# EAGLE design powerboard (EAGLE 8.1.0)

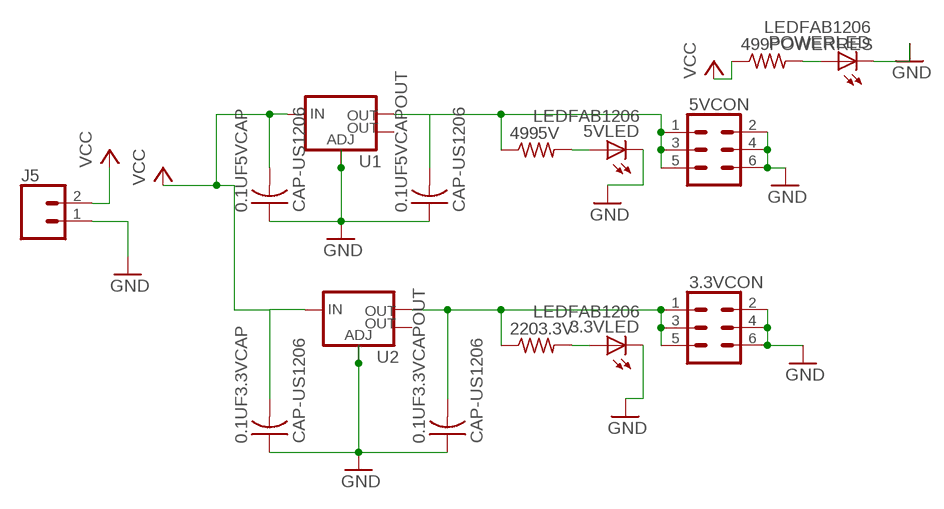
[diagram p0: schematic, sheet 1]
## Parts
0.1UF3.3VCAP  CAP-US1206  [C1206]
0.1UF3.3VCAPOUT  CAP-US1206  [C1206]
0.1UF5VCAP  CAP-US1206  [C1206]
0.1UF5VCAPOUT  CAP-US1206  [C1206]
3.3VCON  CONN_03X22X3_SILK_MALE_PTH  [2X3]
3.3VLED  LEDFAB1206  [LED1206FAB]
5VCON  CONN_03X22X3_SILK_MALE_PTH  [2X3]
5VLED  LEDFAB1206  [LED1206FAB]
499POWERRES  RES-US1206FAB  [R1206FAB]
2203.3V  RES-US1206FAB  [R1206FAB]
4995V  RES-US1206FAB  [R1206FAB]
J5  CONN_02PTH3  [1X02_LONGPADS]
POWERLED  LEDFAB1206  [LED1206FAB]
U1  V_REG_LM1117SOT223  [SOT223]
U2  V_REG_LM1117SOT223  [SOT223]

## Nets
3.3VOUT: 0.1UF3.3VCAPOUT.2 3.3VCON.1 3.3VCON.3 3.3VCON.5 2203.3V.1 U2.2(OUT)
5VOUT: 0.1UF5VCAPOUT.2 5VCON.1 5VCON.3 5VCON.5 4995V.1 U1.2(OUT)
GND: 0.1UF3.3VCAP.1 0.1UF3.3VCAPOUT.1 0.1UF5VCAP.1 0.1UF5VCAPOUT.1 3.3VCON.2 3.3VCON.4 3.3VCON.6 3.3VLED.2(C) 5VCON.2 5VCON.4 5VCON.6 5VLED.2(C) J5.1 POWERLED.2(C) U1.1(ADJ) U2.1(ADJ)
N$1: 5VLED.1(A) 4995V.2
N$3: 499POWERRES.2 POWERLED.1(A)
N$4: 3.3VLED.1(A) 2203.3V.2
VCC: 0.1UF3.3VCAP.2 0.1UF5VCAP.2 499POWERRES.1 J5.2 U1.3(IN) U2.3(IN)
Unconnected: U1.4(OUT) U2.4(OUT)

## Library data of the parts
0.1UF3.3VCAP 0.1UF3.3VCAPOUT 0.1UF5VCAP 0.1UF5VCAPOUT = fab:CAP-US
3.3VCON 5VCON = SparkFun-Connectors:CONN_03X2: Multi connection point. Often used as Generic Header-pin footprint for 0.1 inch spaced/style header connections You can populate with any combo of single row headers, but if you'd like an exact match, check these: Header - 2x3 (Male, 0.1") (PRT-12807) Header - 2x3 (Female, 0.1") (PRT-13010) 2x3 Pin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; PROD_ID: CONN-09701
3.3VLED 5VLED POWERLED = fab:LED: LED
499POWERRES 2203.3V 4995V = fab:RES-US: Resistor (US Symbol)
J5 = SparkFun-Connectors:CONN_02: Multi connection point. Often used as Generic Header-pin footprint for 0.1 inch spaced/style header connections
U1 U2 = fab:V_REG_LM1117: Voltage Regulator LM1117 Standard adjustable voltage regulator but in SMD form. Spark Fun Electronics SKU : COM-00595; PROD_ID: VREG-08170

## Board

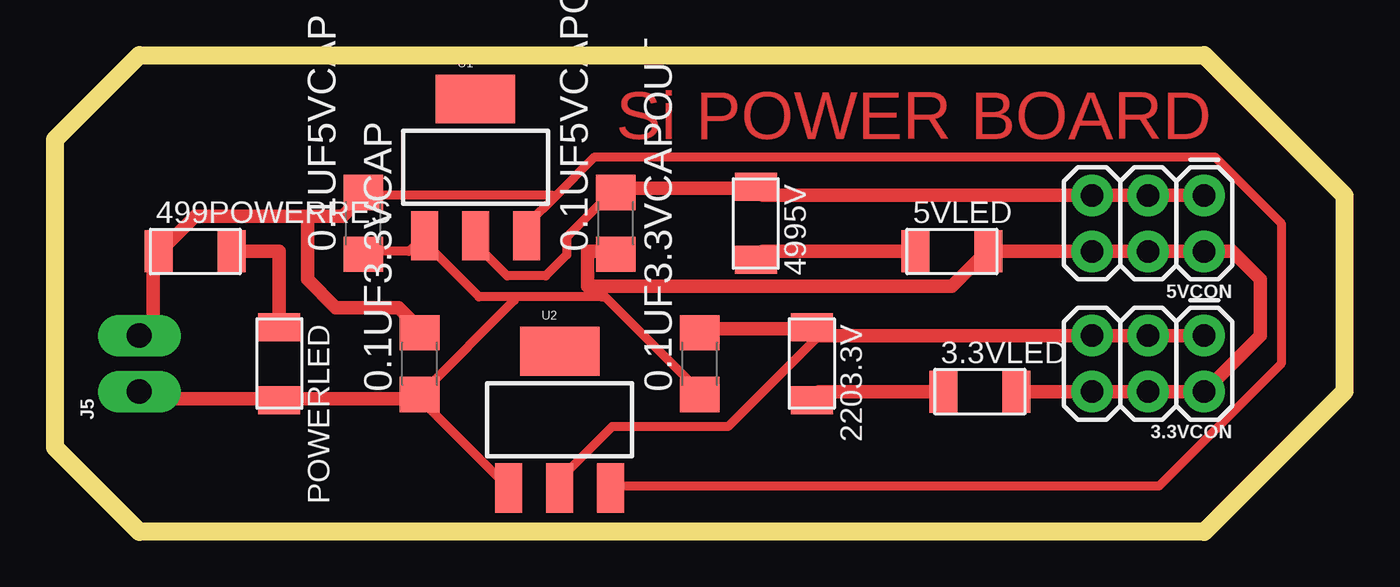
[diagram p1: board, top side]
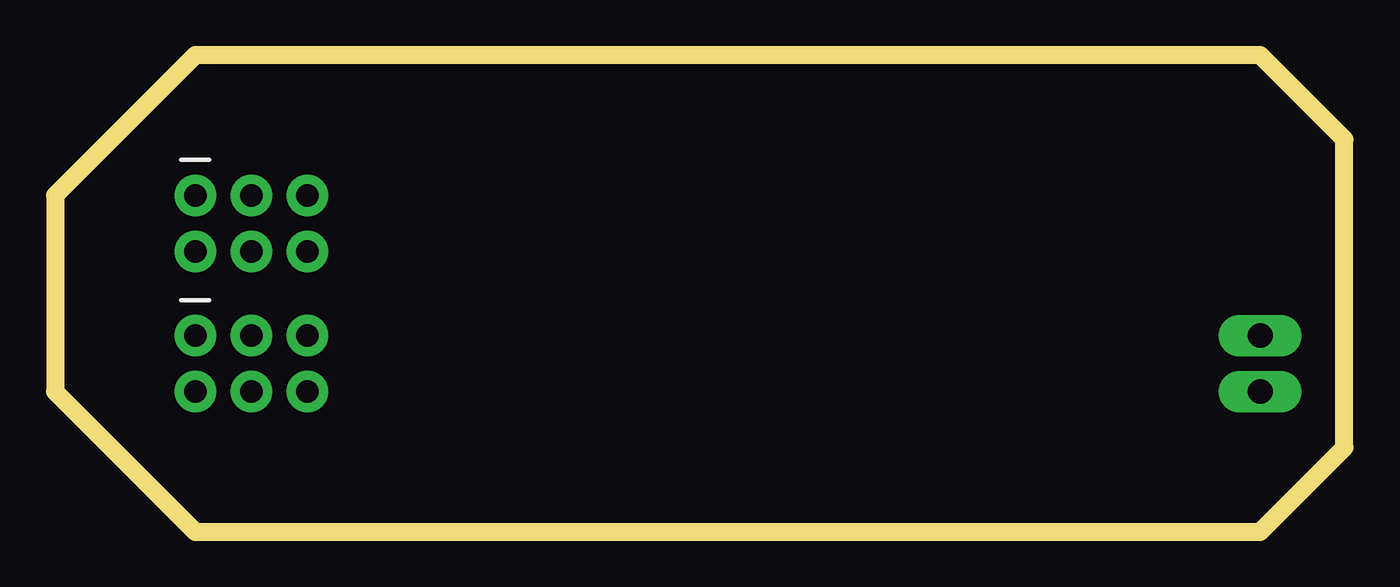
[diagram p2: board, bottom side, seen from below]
Size 58.42 x 21.59 mm. Coordinates in mm from the lower left corner, seen from the top.
Outline: 3.81,21.59 52.07,21.59 58.42,15.24 58.42,6.35 52.07,0 3.81,0 0,3.81 0,17.78 3.81,21.59
Copper layers (1*16): Top 0.035mm / dielectric 1.5mm / Bottom 0.035mm
Design rules "default *": minimum track width 16mil, minimum drill 24mil, track to track 16mil, track to pad 16mil, pad to pad 16mil, via to via 16mil, smd to smd 8mil, copper to edge 40mil, drill to drill 16mil, minimum pad ring 10mil, minimum via ring 8mil, stop-mask expansion 4mil, vias tented up to drill 0mil, thermal gap 10mil

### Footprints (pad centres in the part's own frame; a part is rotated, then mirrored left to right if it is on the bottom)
C1206 = smd 1.6 x 1.8: 1 -1.4,0; 2 1.4,0
2X3 = drill 1.016 pad 1.88: 1 0,0; 2 0,2.54; 3 2.54,0; 4 2.54,2.54; 5 5.08,0; 6 5.08,2.54
LED1206FAB = smd 1.27 x 1.905: 1 -1.651,0; 2 1.651,0
R1206FAB = smd 1.27 x 1.905: 1 -1.651,0; 2 1.651,0
1X02_LONGPADS = drill 1.118 pad 1.88 long: 1 0,0; 2 2.54,0
SOT223 = smd 1.219 x 2.235: 1 -2.311,-3.099; 2 0,-3.099; 3 2.311,-3.099 | smd 3.6 x 2.2: 4 0,3.099

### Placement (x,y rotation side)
0.1UF3.3VCAP  16.51,7.62 90 top
0.1UF3.3VCAPOUT  29.21,7.62 90 top
0.1UF5VCAP  13.97,13.97 90 top
0.1UF5VCAPOUT  25.4,13.97 90 top
3.3VCON  52.07,8.89 180 top
3.3VLED  41.91,6.35 0 top
5VCON  52.07,15.24 180 top
5VLED  40.64,12.7 0 top
499POWERRES  6.35,12.7 0 top
2203.3V  34.29,7.62 270 top
4995V  31.75,13.97 270 top
J5  3.81,6.35 90 top
POWERLED  10.16,7.62 270 top
U1  19.05,16.51 0 top
U2  22.86,5.08 0 top

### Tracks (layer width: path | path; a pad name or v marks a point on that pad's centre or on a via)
3.3VOUT
  Top 0.254: 29.21,9.21 0.1UF3.3VCAPOUT.2 | 34.61,8.89 34.29,9.21 2203.3V.1
  Top 0.406: U2.2 22.86,2.38 25.24,4.76 30.48,4.76 34.45,8.73 2203.3V.1
  Top 0.61: 29.21,8.89 0.1UF3.3VCAPOUT.2 | 29.21,9.21 34.29,9.21 | 3.3VCON.1 3.3VCON.3 3.3VCON.5 34.61,8.89
5VOUT
  Top 0.254: 25.4,15.56 0.1UF5VCAPOUT.2 | 32.07,15.24 31.75,15.56 4995V.1
  Top 0.406: U1.2 19.05,13.02 20.48,11.59 22.23,11.59 23.18,12.54 23.18,13.34 25.24,15.4 0.1UF5VCAPOUT.2
  Top 0.61: 25.4,15.56 31.75,15.56 | 5VCON.1 5VCON.3 5VCON.5 32.07,15.24
GND
  Top 0.254: 16.51,6.03 0.1UF3.3VCAP.1 16.51,6.35 | 4.13,6.03 J5.1 | 10.16,6.03 POWERLED.2 | 25.4,12.7 0.1UF5VCAPOUT.1 | 42.23,12.7 5VLED.2
  Top 0.406: U2.1 20.48,2.06 16.67,5.87 0.1UF3.3VCAP.1 16.67,6.35 20.8,10.48 20.8,10.64 | 0.1UF5VCAP.1 13.97,12.7 16.03,12.7 16.67,13.34 U1.1 16.67,13.18 19.21,10.64 20.8,10.64 | 24.84,10.72 24.61,10.95 24.61,11.11 | 24.84,10.72 29.21,6.35 0.1UF3.3VCAPOUT.1 | 20.8,10.64 24.77,10.64 24.84,10.72
  Top 0.61: 3.3VLED.2 3.3VCON.6 3.3VCON.4 3.3VCON.2 54.61,8.89 54.61,11.43 53.34,12.7 5VCON.2 5VCON.4 5VCON.6 5VLED.2 | 16.51,6.03 10.16,6.03 4.13,6.03 | 25.4,12.7 24.13,12.7 24.13,11.11 24.61,11.11 40.64,11.11 42.23,12.7
N$1
  Top 0.254: 32.07,12.7 31.75,12.38
  Top 0.61: 5VLED.1 32.07,12.7 | 31.75,12.38 4995V.2
N$3
  Top 0.61: POWERLED.1 10.16,12.7 499POWERRES.2
N$4
  Top 0.254: 34.61,6.35 34.29,6.03 2203.3V.2
  Top 0.61: 3.3VLED.1 34.61,6.35
VCC
  Top 0.254: 16.51,8.89 0.1UF3.3VCAP.2 16.51,9.21 | 13.97,15.56 0.1UF5VCAP.2 13.97,15.24 | J5.2 4.45,8.89 | 4.45,12.7 499POWERRES.1 4.76,12.7
  Top 0.406: 22.62,15.16 21.43,13.97 21.43,13.49 U1.3 | 22.62,15.16 24.45,16.99 52.55,16.99 55.56,13.97 55.56,7.62 50.01,2.06 25.24,2.06 U2.3 | 0.1UF5VCAP.2 14.13,15.24 22.54,15.24 22.62,15.16
  Top 0.61: 4.45,8.89 4.45,12.7 | 13.97,15.24 13.02,14.29 11.43,14.29 | 11.43,14.29 6.35,14.29 4.76,12.7 | 16.51,9.21 15.56,10.16 12.7,10.16 11.43,11.43 11.43,14.29

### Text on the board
Top: Si POWER BOARD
